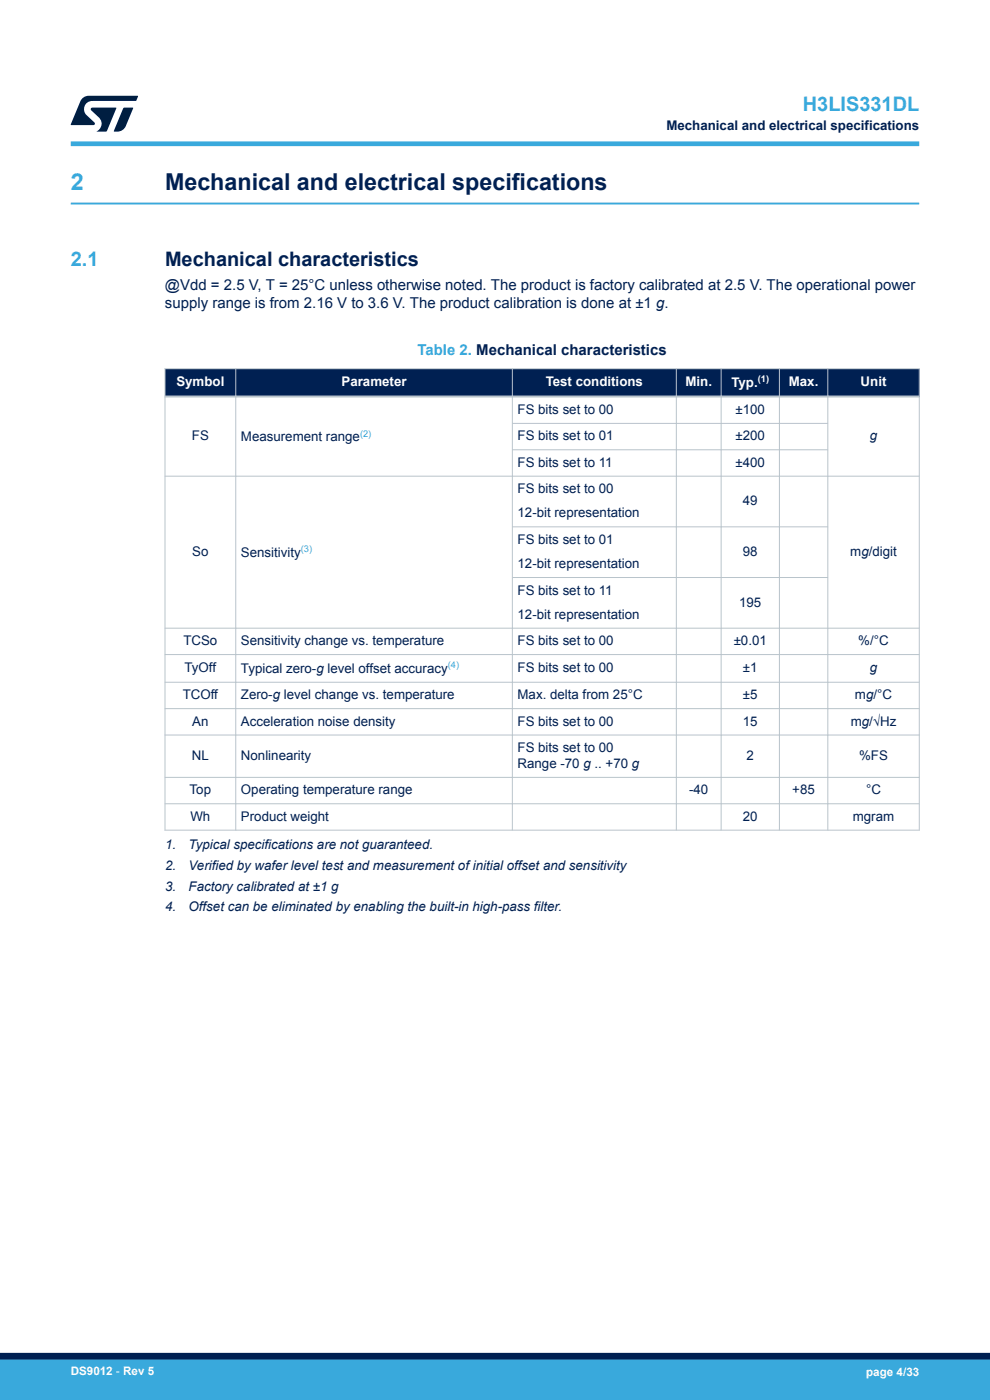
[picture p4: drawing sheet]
<svg xmlns="http://www.w3.org/2000/svg" width="210mm" height="297mm" viewBox="0 0 210 297" stroke-linecap="round" stroke-linejoin="round" font-family="sans-serif">
<defs><g id="words">
<text font-size="4.9" fill="#39a9dc" x="15" y="40.4">2</text>
<text font-size="4.9" fill="#002052" x="35" y="40.4">Mechanical and electrical specifications</text>
<g font-size="4.2" fill="#39a9dc">
<text x="170.3" y="23.5">H3LIS331DL</text>
<text x="15" y="56.4">2.1</text>
</g>
<text font-size="4.2" fill="#002052" x="35" y="56.4">Mechanical characteristics</text>
<g font-size="3.2" fill="#002052">
<text x="35" y="61.5">@Vdd = 2.5 V, T = 25°C unless otherwise noted. The product is factory calibrated at 2.5 V. The operational power</text>
<text x="35" y="65.3">supply range is from 2.16 V to 3.6 V. The product calibration is done at ±1 g.</text>
</g>
<text font-size="3.2" fill="#39a9dc" x="88.6" y="75.2">Table 2. Mechanical characteristics</text>
<g font-size="2.8" fill="#002052">
<text x="141.4" y="27.5">Mechanical and electrical specifications</text>
<text x="109.8" y="87.8">FS bits set to 00</text>
<text x="156" y="87.8">±100</text>
<text x="40.7" y="93.4">FS</text>
<text x="51.1" y="93.6">Measurement range</text>
<text x="109.8" y="93.4">FS bits set to 01</text>
<text x="156" y="93.4">±200</text>
<text x="184.5" y="93.4">g</text>
<text x="109.8" y="99">FS bits set to 11</text>
<text x="156" y="99">±400</text>
<text x="109.8" y="104.6">FS bits set to 00</text>
<text x="157.6" y="107.2">49</text>
<text x="109.8" y="109.8">12-bit representation</text>
<text x="40.8" y="118">So</text>
<text x="51.1" y="118.1">Sensitivity</text>
<text x="109.8" y="115.4">FS bits set to 01</text>
<text x="157.6" y="118">98</text>
<text x="180.4" y="118">mg/digit</text>
<text x="109.8" y="120.5">12-bit representation</text>
<text x="109.8" y="126.1">FS bits set to 11</text>
<text x="109.8" y="131.3">12-bit representation</text>
<text x="156.8" y="128.7">195</text>
<text x="38.9" y="136.9">TCSo</text>
<text x="51.1" y="136.9">Sensitivity change vs. temperature</text>
<text x="109.8" y="136.9">FS bits set to 00</text>
<text x="155.6" y="136.9">±0.01</text>
<text x="182.1" y="136.9">%/°C</text>
<text x="39.2" y="142.6">TyOff</text>
<text x="51.1" y="142.7">Typical zero-g level offset accuracy</text>
<text x="109.8" y="142.6">FS bits set to 00</text>
<text x="157.6" y="142.6">±1</text>
<text x="184.5" y="142.6">g</text>
<text x="38.8" y="148.3">TCOff</text>
<text x="51.1" y="148.3">Zero-g level change vs. temperature</text>
<text x="109.8" y="148.3">Max. delta from 25°C</text>
<text x="157.6" y="148.3">±5</text>
<text x="181.4" y="148.3">mg/°C</text>
<text x="40.8" y="153.9">An</text>
<text x="51.1" y="153.9">Acceleration noise density</text>
<text x="109.8" y="153.9">FS bits set to 00</text>
<text x="157.6" y="153.9">15</text>
<text x="180.4" y="153.9">mg/√Hz</text>
<text x="40.7" y="161.2">NL</text>
<text x="51.1" y="161.2">Nonlinearity</text>
<text x="109.8" y="159.5">FS bits set to 00</text>
<text x="158.4" y="161.2">2</text>
<text x="182.2" y="161.2">%FS</text>
<text x="109.8" y="162.9">Range -70 g .. +70 g</text>
<text x="40.2" y="168.5">Top</text>
<text x="51.1" y="168.5">Operating temperature range</text>
<text x="146.2" y="168.5">-40</text>
<text x="168.1" y="168.5">+85</text>
<text x="183.7" y="168.5">°C</text>
<text x="40.4" y="174.1">Wh</text>
<text x="51.1" y="174.1">Product weight</text>
<text x="157.6" y="174.1">20</text>
<text x="180.9" y="174.1">mgram</text>
<text x="35" y="180.2">1.</text>
<text x="35" y="184.5">2.</text>
<text x="40" y="180.2">Typical specifications are not guaranteed.</text>
<text x="40" y="184.5">Verified by wafer level test and measurement of initial offset and sensitivity</text>
<text x="35" y="188.9">3.</text>
<text x="40" y="188.9">Factory calibrated at ±1 g</text>
<text x="35" y="193.3">4.</text>
<text x="40" y="193.3">Offset can be eliminated by enabling the built-in high-pass filter.</text>
</g>
<g font-size="2.8" fill="#fff">
<text x="37.4" y="81.9">Symbol</text>
<text x="72.4" y="81.9">Parameter</text>
<text x="115.7" y="81.9">Test conditions</text>
<text x="145.4" y="81.9">Min.</text>
<text x="155.1" y="82">Typ.</text>
<text x="167.3" y="81.9">Max.</text>
<text x="182.6" y="81.9">Unit</text>
</g>
<g font-size="2.5" fill="#fff">
<text x="15" y="291.6">DS9012 - Rev 5</text>
<text x="183.7" y="291.9">page 4/33</text>
</g>
<text font-size="2" fill="#fff" x="160.7" y="81.1">(1)</text>
<g font-size="2" fill="#39a9dc">
<text x="76.4" y="92.6">(2)</text>
<text x="63.8" y="117.2">(3)</text>
<text x="95" y="141.8">(4)</text>
</g>
</g></defs>
<path d="M15 43.2h180" fill="none" stroke="#39a9dc" stroke-width=".4"/>
<g fill="#002052">
<path d="M35 78.2h160v5.9h-160z" fill-rule="evenodd"/>
<path d="M35 78.2h160v5.9h-160z" fill-rule="evenodd"/>
</g>
<g fill="none" stroke="#b9c4ca" stroke-width=".21">
<path d="M34.9 78.2h160.2M35 78.1v98.1M50 78.1v98.1M108.7 78.1v98.1M143.5 78.1v98.1M153 78.1v98.1M165.3 78.1v98.1M175.6 78.1v98.1M195 78.1v98.1M108.7 89.8h67M108.7 95.4h67M34.9 101h160.2"/>
<path d="M108.7 111.8h67M34.9 133.3h160.2M34.9 138.9h160.2M108.7 122.5h67M34.9 144.7h160.2M34.9 150.3h160.2M34.9 155.9h160.2M34.9 164.9h160.2M34.9 170.5h160.2M34.9 176.1h160.2"/>
</g>
<path d="M34.9 84.1h160.2" fill="none" stroke="#b9c4ca" stroke-width=".42"/>
<path d="M15 30.5h180" fill="none" stroke="#39a9dc" stroke-width="1"/>
<g fill="#001e41">
<path d="M17.6 20.8l1.2-.5 10.5 .1-.5 1h-9.2a1.74 1.74 0 0 0-1.6 1 1.74 1.74 0 0 0 .3 2l1.7 1.6 .1 .2-.1 .3h-5l2.1-5z"/>
<path d="M26.2 22.9h2.1l-1.6 3.9a1.92 1.92 0 0 1-1.8 1.1h-.7l-.1-.1z"/>
<path d="M19.4 22.9l5.2-.1 .1 .1-2.1 5h-2.1a1.85 1.85 0 0 0 .5-2.9l-1.6-1.6-.2-.2z"/>
</g>
<g fill="#39a9dc">
<path d="M0 288.4h210v8.6h-210z" fill-rule="evenodd"/>
<path d="M-.1 288.4h210.2v4.4h-210.2z" fill-rule="evenodd"/>
</g>
<path d="M0 287.7h210" fill="none" stroke="#002052" stroke-width="1.4"/>
<use href="#words"/>
</svg>
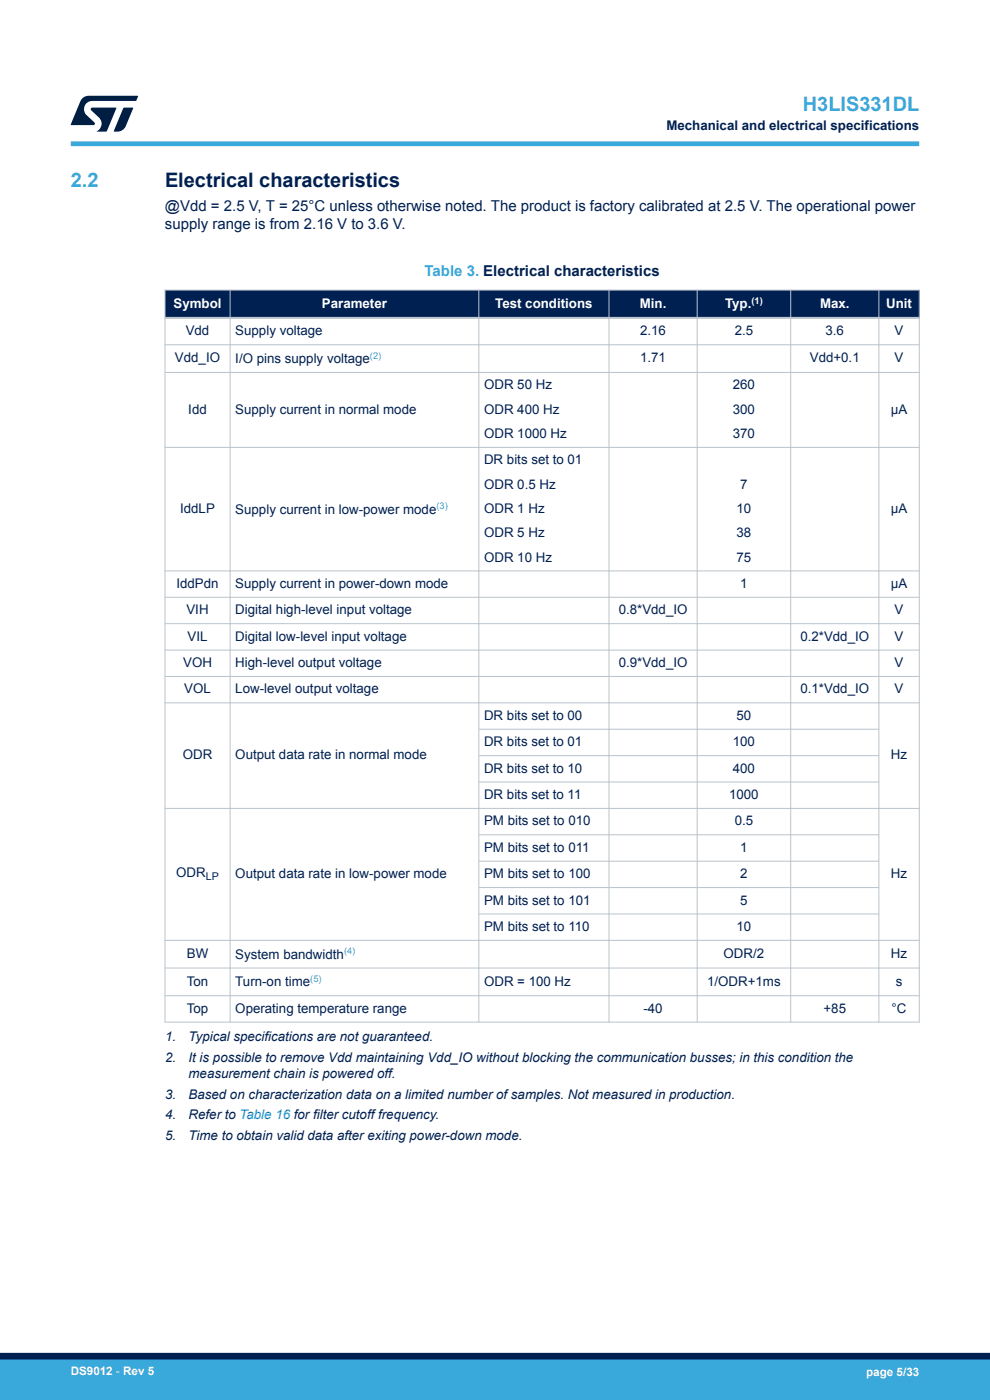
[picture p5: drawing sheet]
<svg xmlns="http://www.w3.org/2000/svg" width="210mm" height="297mm" viewBox="0 0 210 297" stroke-linecap="round" stroke-linejoin="round" font-family="sans-serif">
<defs><g id="words">
<g font-size="4.2" fill="#39a9dc">
<text x="170.3" y="23.5">H3LIS331DL</text>
<text x="15" y="39.8">2.2</text>
</g>
<text font-size="4.2" fill="#002052" x="35" y="39.8">Electrical characteristics</text>
<g font-size="3.2" fill="#002052">
<text x="35" y="44.8">@Vdd = 2.5 V, T = 25°C unless otherwise noted. The product is factory calibrated at 2.5 V. The operational power</text>
<text x="35" y="48.6">supply range is from 2.16 V to 3.6 V.</text>
</g>
<text font-size="3.2" fill="#39a9dc" x="90.1" y="58.6">Table 3. Electrical characteristics</text>
<g font-size="2.8" fill="#002052">
<text x="141.4" y="27.5">Mechanical and electrical specifications</text>
<text x="39.4" y="71.2">Vdd</text>
<text x="49.9" y="71.2">Supply voltage</text>
<text x="135.8" y="71.2">2.16</text>
<text x="155.8" y="71.2">2.5</text>
<text x="175.1" y="71.2">3.6</text>
<text x="189.8" y="71.2">V</text>
<text x="37.1" y="76.9">Vdd_IO</text>
<text x="49.9" y="77">I/O pins supply voltage</text>
<text x="135.8" y="76.9">1.71</text>
<text x="171.8" y="76.9">Vdd+0.1</text>
<text x="189.8" y="76.9">V</text>
<text x="102.7" y="82.6">ODR 50 Hz</text>
<text x="155.5" y="82.6">260</text>
<text x="39.9" y="87.8">Idd</text>
<text x="49.9" y="87.8">Supply current in normal mode</text>
<text x="102.7" y="87.8">ODR 400 Hz</text>
<text x="155.5" y="87.8">300</text>
<text x="189" y="87.8">µA</text>
<text x="102.7" y="92.9">ODR 1000 Hz</text>
<text x="155.5" y="92.9">370</text>
<text x="102.7" y="98.5">DR bits set to 01</text>
<text x="102.7" y="103.7">ODR 0.5 Hz</text>
<text x="157" y="103.7">7</text>
<text x="38.2" y="108.8">IddLP</text>
<text x="49.9" y="109">Supply current in low-power mode</text>
<text x="102.7" y="108.8">ODR 1 Hz</text>
<text x="102.7" y="114">ODR 5 Hz</text>
<text x="156.2" y="108.8">10</text>
<text x="156.2" y="114">38</text>
<text x="189" y="108.8">µA</text>
<text x="102.7" y="119.1">ODR 10 Hz</text>
<text x="156.2" y="119.1">75</text>
<text x="37.4" y="124.7">IddPdn</text>
<text x="49.9" y="124.7">Supply current in power-down mode</text>
<text x="157" y="124.7">1</text>
<text x="189" y="124.7">µA</text>
<text x="39.6" y="130.3">VIH</text>
<text x="49.9" y="130.3">Digital high-level input voltage</text>
<text x="131.2" y="130.3">0.8*Vdd_IO</text>
<text x="189.8" y="130.3">V</text>
<text x="39.8" y="135.9">VIL</text>
<text x="49.9" y="135.9">Digital low-level input voltage</text>
<text x="169.8" y="135.9">0.2*Vdd_IO</text>
<text x="189.8" y="135.9">V</text>
<text x="38.8" y="141.5">VOH</text>
<text x="49.9" y="141.5">High-level output voltage</text>
<text x="131.2" y="141.5">0.9*Vdd_IO</text>
<text x="189.8" y="141.5">V</text>
<text x="39.1" y="147.1">VOL</text>
<text x="49.9" y="147.1">Low-level output voltage</text>
<text x="169.8" y="147.1">0.1*Vdd_IO</text>
<text x="189.8" y="147.1">V</text>
<text x="102.7" y="152.7">DR bits set to 00</text>
<text x="156.2" y="152.7">50</text>
<text x="38.8" y="161.1">ODR</text>
<text x="49.9" y="161.1">Output data rate in normal mode</text>
<text x="102.7" y="158.3">DR bits set to 01</text>
<text x="155.5" y="158.3">100</text>
<text x="189" y="161.1">Hz</text>
<text x="102.7" y="163.9">DR bits set to 10</text>
<text x="155.5" y="163.9">400</text>
<text x="102.7" y="169.5">DR bits set to 11</text>
<text x="154.7" y="169.5">1000</text>
<text x="102.7" y="175.1">PM bits set to 010</text>
<text x="155.8" y="175.1">0.5</text>
<text x="102.7" y="180.7">PM bits set to 011</text>
<text x="157" y="180.7">1</text>
<text x="37.4" y="186.1">ODR</text>
<text x="49.9" y="186.3">Output data rate in low-power mode</text>
<text x="102.7" y="186.3">PM bits set to 100</text>
<text x="102.7" y="191.9">PM bits set to 101</text>
<text x="157" y="186.3">2</text>
<text x="157" y="191.9">5</text>
<text x="189" y="186.3">Hz</text>
<text x="102.7" y="197.5">PM bits set to 110</text>
<text x="156.2" y="197.5">10</text>
<text x="39.6" y="203.2">BW</text>
<text x="49.9" y="203.4">System bandwidth</text>
<text x="153.5" y="203.2">ODR/2</text>
<text x="189" y="203.2">Hz</text>
<text x="39.6" y="209.1">Ton</text>
<text x="49.9" y="209.2">Turn-on time</text>
<text x="102.7" y="209.1">ODR = 100 Hz</text>
<text x="150" y="209.1">1/ODR+1ms</text>
<text x="190" y="209.1">s</text>
<text x="39.6" y="214.8">Top</text>
<text x="49.9" y="214.8">Operating temperature range</text>
<text x="136.5" y="214.8">-40</text>
<text x="174.7" y="214.8">+85</text>
<text x="189.1" y="214.8">°C</text>
<text x="35" y="220.9">1.</text>
<text x="40" y="220.9">Typical specifications are not guaranteed.</text>
<text x="35" y="225.3">2.</text>
<text x="40" y="225.3">It is possible to remove Vdd maintaining Vdd_IO without blocking the communication busses; in this condition the</text>
<text x="35" y="233">3.</text>
<text x="40" y="228.7">measurement chain is powered off.</text>
<text x="40" y="233">Based on characterization data on a limited number of samples. Not measured in production.</text>
<text x="35" y="237.4">4.</text>
<text x="40" y="237.4">Refer to Table 16 for filter cutoff frequency.</text>
<text x="35" y="241.8">5.</text>
<text x="40" y="241.8">Time to obtain valid data after exiting power-down mode.</text>
</g>
<g font-size="2.8" fill="#fff">
<text x="36.8" y="65.3">Symbol</text>
<text x="68.3" y="65.3">Parameter</text>
<text x="105.1" y="65.3">Test conditions</text>
<text x="135.7" y="65.3">Min.</text>
<text x="153.8" y="65.3">Typ.</text>
<text x="173.9" y="65.3">Max.</text>
<text x="188" y="65.3">Unit</text>
</g>
<g font-size="2.5" fill="#fff">
<text x="15" y="291.6">DS9012 - Rev 5</text>
<text x="183.7" y="291.9">page 5/33</text>
</g>
<text font-size="2.3" fill="#002052" x="43.7" y="186.6">LP</text>
<text font-size="2" fill="#fff" x="159.4" y="64.4">(1)</text>
<g font-size="2" fill="#39a9dc">
<text x="78.5" y="76.1">(2)</text>
<text x="92.6" y="108">(3)</text>
<text x="73" y="202.4">(4)</text>
<text x="65.8" y="208.3">(5)</text>
</g>
</g></defs>
<g fill="#002052">
<path d="M35 61.5h160v5.9h-160z" fill-rule="evenodd"/>
<path d="M35 61.5h160v5.9h-160z" fill-rule="evenodd"/>
</g>
<g fill="none" stroke="#b9c4ca" stroke-width=".21">
<path d="M34.9 61.5h160.2M34.9 73.1h160.2M34.9 79h160.2M35 61.4v155.5M48.8 61.4v155.5M101.6 61.4v155.5M129.2 61.4v155.5M147.9 61.4v155.5M167.7 61.4v155.5M186.4 61.4v155.5M195 61.4v155.5M34.9 94.9h160.2"/>
<path d="M34.9 121.1h160.2M34.9 126.7h160.2M34.9 132.3h160.2M34.9 137.9h160.2M34.9 143.5h160.2M34.9 149.1h160.2M101.6 154.7h84.9M34.9 171.5h160.2M101.6 160.3h84.9M101.6 165.9h84.9M101.6 177.1h84.9M34.9 199.5h160.2"/>
<path d="M101.6 182.7h84.9M101.6 188.3h84.9M101.6 193.9h84.9M34.9 205.4h160.2M34.9 211.2h160.2M34.9 216.8h160.2"/>
</g>
<path d="M34.9 67.4h160.2" fill="none" stroke="#b9c4ca" stroke-width=".42"/>
<path d="M15 30.5h180" fill="none" stroke="#39a9dc" stroke-width="1"/>
<g fill="#001e41">
<path d="M17.6 20.8l1.2-.5 10.5 .1-.5 1h-9.2a1.74 1.74 0 0 0-1.6 1 1.74 1.74 0 0 0 .3 2l1.7 1.6 .1 .2-.1 .3h-5l2.1-5z"/>
<path d="M26.2 22.9h2.1l-1.6 3.9a1.92 1.92 0 0 1-1.8 1.1h-.7l-.1-.1z"/>
<path d="M19.4 22.9l5.2-.1 .1 .1-2.1 5h-2.1a1.85 1.85 0 0 0 .5-2.9l-1.6-1.6-.2-.2z"/>
</g>
<g fill="#39a9dc">
<path d="M0 288.4h210v8.6h-210z" fill-rule="evenodd"/>
<path d="M-.1 288.4h210.2v4.4h-210.2z" fill-rule="evenodd"/>
</g>
<path d="M0 287.7h210" fill="none" stroke="#002052" stroke-width="1.4"/>
<use href="#words"/>
</svg>
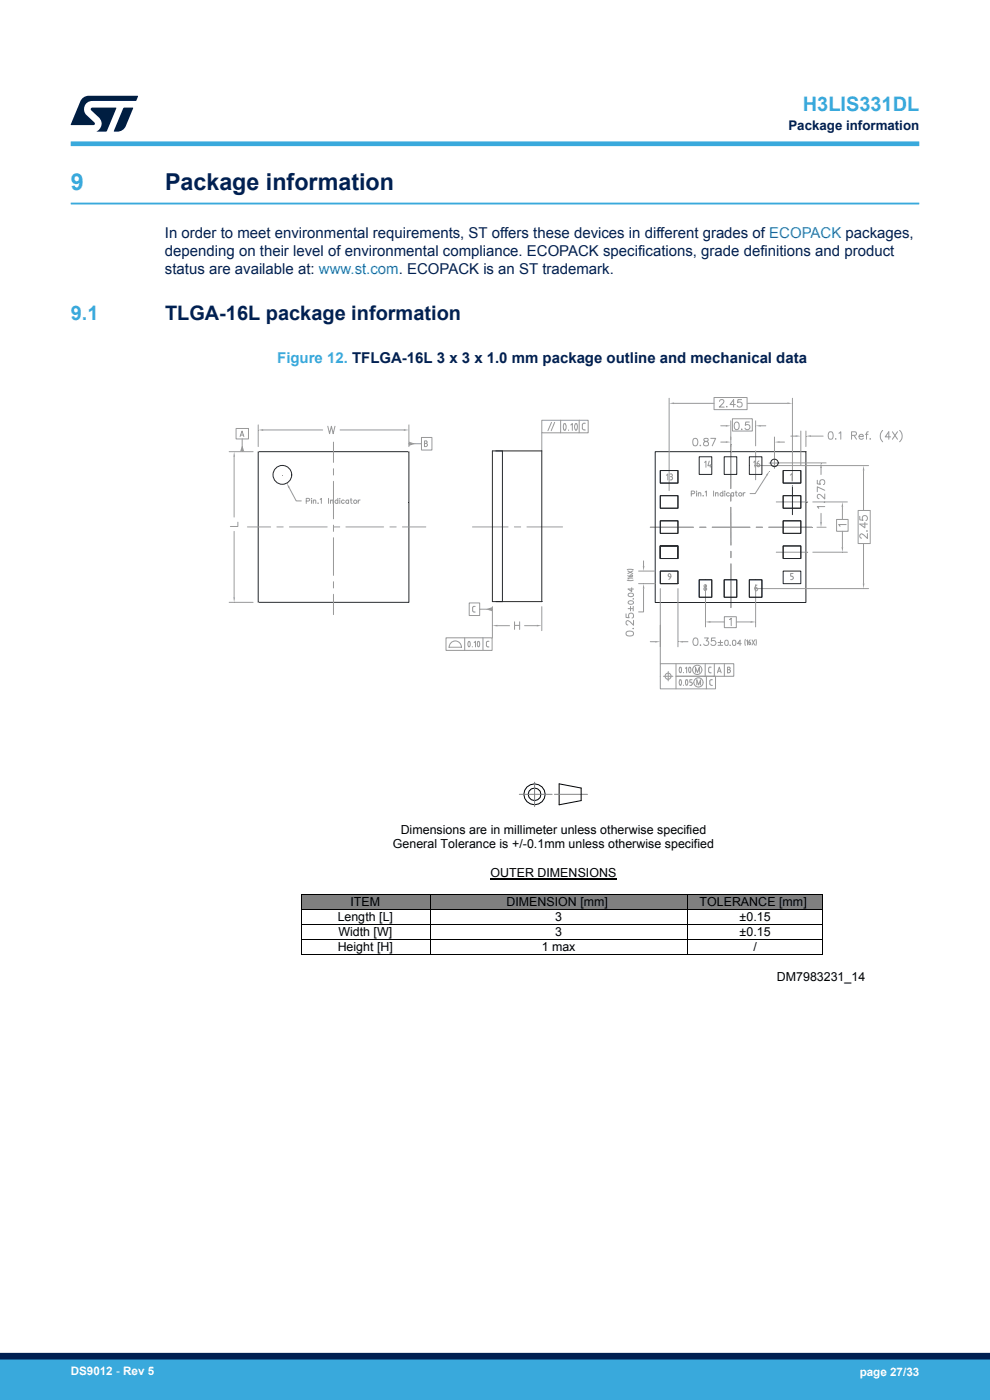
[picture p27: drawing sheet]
<svg xmlns="http://www.w3.org/2000/svg" width="210mm" height="297mm" viewBox="0 0 210 297" stroke-linecap="round" stroke-linejoin="round" font-family="sans-serif">
<defs><g id="words">
<text font-size="4.9" fill="#39a9dc" x="15" y="40.4">9</text>
<text font-size="4.9" fill="#002052" x="35" y="40.4">Package information</text>
<g font-size="4.2" fill="#39a9dc">
<text x="170.3" y="23.5">H3LIS331DL</text>
<text x="15" y="67.9">9.1</text>
</g>
<text font-size="4.2" fill="#002052" x="35" y="67.9">TLGA-16L package information</text>
<g font-size="3.2" fill="#002052">
<text x="35" y="50.5">In order to meet environmental requirements, ST offers these devices in different grades of ECOPACK packages,</text>
<text x="35" y="54.3">depending on their level of environmental compliance. ECOPACK specifications, grade definitions and product</text>
<text x="35" y="58.1">status are available at: www.st.com. ECOPACK is an ST trademark.</text>
</g>
<text font-size="3.2" fill="#39a9dc" x="58.8" y="77">Figure 12. TFLGA-16L 3 x 3 x 1.0 mm package outline and mechanical data</text>
<text font-size="2.8" fill="#002052" x="167.2" y="27.5">Package information</text>
<g font-size="2.6">
<text x="85" y="177">Dimensions are in millimeter unless otherwise specified</text>
<text x="83.3" y="180">General Tolerance is +/-0.1mm unless otherwise specified</text>
<text x="104" y="186.1">OUTER DIMENSIONS</text>
<text x="71.6" y="195.5">Length [L]</text>
<text x="74.4" y="192.3">ITEM</text>
<text x="107.4" y="192.3">DIMENSION [mm]</text>
<text x="117.8" y="195.5">3</text>
<text x="148.4" y="192.3">TOLERANCE [mm]</text>
<text x="156.9" y="195.5">±0.15</text>
<text x="71.6" y="201.8">Height [H]</text>
<text x="71.8" y="198.6">Width [W]</text>
<text x="114.9" y="201.8">1 max</text>
<text x="117.8" y="198.6">3</text>
<text x="156.9" y="198.6">±0.15</text>
<text x="159.8" y="201.8">/</text>
<text x="164.8" y="208.2">DM7983231_14</text>
</g>
<g font-size="2.5" fill="#fff">
<text x="15" y="291.6">DS9012 - Rev 5</text>
<text x="182.4" y="291.9">page 27/33</text>
</g>
</g></defs>
<path d="M15 43.2h180" fill="none" stroke="#39a9dc" stroke-width=".4"/>
<path d="M155 94.3v9.3M137.9 111.9h9.2M148.4 111.9h1.3M151.1 111.9h8M155 107.6v8M155 105v1.3M155 117v1.3M155 119.6v9.3M160.4 111.9h1.3M163.1 111.9h9.1" fill="none" stroke="#999" stroke-width=".21"/>
<path d="M54.8 95.8h31.9v32h-31.9z" fill="none" stroke="#222831" stroke-width=".21"/>
<path d="M54.8 90.1v4.6M55.8 91.2h12.7M72.1 91.2h13.6M86.7 90.1v4.6" fill="none" stroke="#999" stroke-width=".21"/>
<g fill="#999">
<path d="M85.7 91l1 .2-1 .2z"/>
<path d="M54.8 91.2l1-.2v.4z"/>
</g>
<path d="M48.6 95.8h5.1M49.7 96.9v12.8M69.5 90.4l.4 1.6 .4-1.6 .4 1.6 .4-1.6M49.7 112.7v14M48.6 127.8h5.1" fill="none" stroke="#999" stroke-width=".21"/>
<g fill="#999">
<path d="M49.7 95.8l.2 1.1h-.4z"/>
<path d="M49.5 126.7h.4l-.2 1.1z"/>
</g>
<g fill="none" stroke="#999" stroke-width=".21">
<path d="M70.7 93.8v4.3M70.7 99.4v1.4M50.5 110.8v.9h-1.6M52.5 111.8h4.9M58.7 111.8h1.4M61.4 111.8h8M70.7 102.1v8M70.7 111.4v1.3M70.7 114.1v8M70.7 111.8h1.4M73.4 111.8h8M82.7 111.8h1.3"/>
<path d="M85.4 111.8h4.9M70.7 123.4v1.3M70.7 126.1v4.3M104.4 128.7v5.1M105.5 132.7h2.6M111.3 132.7h2.6M114.9 128.7v5.1"/>
</g>
<g fill="#999">
<path d="M113.9 132.5l1 .2-1 .2z"/>
<path d="M104.4 132.7l1.1-.2v.4z"/>
</g>
<path d="M86.7 94.1h2.7M89.4 92.8h2.2v2.7h-2.2zM90 94.1l.6 .1v.3l-.2 .2M90.4 94h.1v-.4l-.5-.1v1.2h.4M109.1 131.9v1.6M109.1 132.7h1.1M110.2 131.9v1.6" fill="none" stroke="#999" stroke-width=".21"/>
<path d="M86.7 93.7l1.4 .4-1.4 .5z" fill="#999"/>
<path d="M50.1 90.9h2.6v2.2h-2.6zM50.9 92.6l.4-1.2 .4 1.2M51.1 92.3h.5M51.4 93.1v2.7" fill="none" stroke="#999" stroke-width=".21"/>
<path d="M51.4 94.5l.4 1.3h-.9z" fill="#999"/>
<path d="M99.5 127.9h2.3v2.7h-2.3zM100.5 129.8h.3M100.8 128.6l-.4 .1-.1 .2v.8l.2 .1M101.8 129.2h2.6" fill="none" stroke="#999" stroke-width=".21"/>
<path d="M103.1 129.2l1.3-.4v.9z" fill="#999"/>
<g fill="none" stroke="#999" stroke-width=".21">
<path d="M114.9 89.2h9.9v2.6h-9.9zM114.9 91.8v3.9M117 89.6l-.8 1.8M117.7 89.6l-.8 1.8M118.9 89.2v2.6M119.6 89.9h.1a.81 .81 0 0 1 0 1.4l-.2-.5zM120.6 91.2v.1M121.1 90.2l.3-.3v1.4M122.1 89.9a.8 .8 0 0 1 .2 1.3v.1a.9 .9 0 0 1-.2-1.4zM122.9 89.2v2.6M123.9 91.2h.3M124.2 89.8h-.5l-.2 .3v.8l.4 .3"/>
<path d="M155 94.3v9.3M100.2 111.8h7.6M109.1 111.8h1.3M111.8 111.8h7.5M137.9 111.9h9.2M148.4 111.9h1.3M151.1 111.9h8M155 107.6v8M155 105v1.3M155 117v1.3M155 119.6v9.3M160.4 111.9h1.3"/>
<path d="M163.1 111.9h9.1M94.6 135.3h9.8v2.7h-9.8zM95.8 136.2a1.3 1.3 0 0 1 1.4-.1 1.3 1.3 0 0 1 .7 1.2h-2.6v-.4zM98.6 135.3v2.7M99.4 136.1a.63 .63 0 0 1 0 1.1l-.2-.6 .2-.5M100.2 137.2h.1M100.6 136.3l.3-.3v1.2M101.4 136.1a.63 .63 0 0 1 0 1.1l-.2-.6 .2-.5M102.4 135.3v2.7M103.5 137.2h.2M103.5 136h.2M103.5 136.1l-.3 .3v.7l.3 .1"/>
<path d="M104.4 133.8v1.5"/>
</g>
<path d="M139 95.8h31.9v32h-31.9zM140 115.8h3.8v2.7h-3.8zM168.1 103.1v6.1" fill="none" stroke="#222831" stroke-width=".21"/>
<path d="M160.3 95.7v6.1M136.5 119v1.1M164.7 106.5h6.6M164.7 117.2h6.6M135.5 121.2h3.5M135.5 123.8h3.5M136.5 124.9v4.9h-1" fill="none" stroke="#999" stroke-width=".21"/>
<g fill="#999">
<path d="M136.4 120.1h.3l-.2 1.1z"/>
<path d="M136.5 123.8l.2 1.1h-.3z"/>
</g>
<path d="M132.8 130.2v.8l.7 .1a.56 .56 0 0 1-.1-.9 .56 .56 0 0 1 .9 .1 .56 .56 0 0 1-.2 .8M132.9 134.1l.6-.2a.68 .68 0 0 1 .9 .6 .93 .93 0 0 1-1.6 0zM133.2 129.1h1M133.3 127.6l.4-.2 .6 .2a.56 .56 0 0 1-.4 .7 .56 .56 0 0 1-.7-.4zM133.3 126a.56 .56 0 0 1 .7-.2 .56 .56 0 0 1 .3 .6 .56 .56 0 0 1-.7 .2 .56 .56 0 0 1-.3-.6zM133.7 128.6v1M134.3 127v.1M134.3 128.6v1M134.3 133.3h-.1M134.4 131.6v1l-.8-.7-.5-.2-.2 .1-.1 .5 .1 .2 .3 .1" fill="none" stroke="#999" stroke-width=".21"/>
<path d="M134 124.7v.8l-.8-.5h1.2M149.7 124v9M150.7 131.9h2.9M156.2 131.9h3M160.3 124v9" fill="none" stroke="#999" stroke-width=".21"/>
<g fill="#999">
<path d="M149.7 131.9l1-.1v.3z"/>
<path d="M159.2 131.8l1.1 .1-1.1 .2z"/>
</g>
<path d="M162.7 100.8l-2.5 3.9h-1.1M154.7 131.4l.4-.3v1.6" fill="none" stroke="#999" stroke-width=".21"/>
<path d="M163.2 99.9l-.4 1-.3-.2z" fill="#999"/>
<g fill="none" stroke="#999" stroke-width=".21">
<path d="M146.6 104.7h.6l.1-.4-.7-.1v1M147.7 104.5v.7M147.7 104.2h.1M148.1 104.5v.7M148.1 104.7l.3-.2 .2 .1 .1 .6M149.1 105.2h.1M149.6 104.4l.2-.2v1M151.4 104.2v1M151.8 104.5v.7M151.8 104.7l.2-.2 .3 .1v.6M153.3 104.2v1M153.3 104.7a.34 .34 0 0 0-.5-.1 .34 .34 0 0 0 0 .5 .34 .34 0 0 0 .5 0"/>
<path d="M153.7 104.5v.7M153.7 104.2h.1M154.7 104.7a.34 .34 0 0 0-.5-.1 .34 .34 0 0 0 0 .5 .34 .34 0 0 0 .5 0M155.6 104.5v.7M155.6 104.7a.34 .34 0 0 0-.5-.1 .34 .34 0 0 0 0 .5 .34 .34 0 0 0 .5 0M156 104.5h.3M156.1 104.2v.8l.3 .2"/>
<circle cx="157" cy="104.9" r=".36"/>
</g>
<path d="M152.9 90.3h1.1M155 89.3v4M160.3 89.3v5.3M161.4 90.3h1M157.6 104.5v.7M158.1 104.5l-.5 .3" fill="none" stroke="#999" stroke-width=".21"/>
<g fill="#999">
<path d="M154 90.2l1 .1-1 .2z"/>
<path d="M160.3 90.3l1.1-.1v.3z"/>
</g>
<path d="M156 89.6a.49 .49 0 0 1 .7 .3l.1 .3a.68 .68 0 0 1-.6 1 1.04 1.04 0 0 1-.2-1.6z" fill="none" stroke="#999" stroke-width=".21"/>
<path d="M141.9 84.5v19.6M143 85.6h8.5M155.4 88.8h4.2v2.6h-4.2zM157.3 91v.2l.1-.1M158.5 85.6h8.5M159 89.5h-.8l-.1 .7a.56 .56 0 0 1 .8 0 .56 .56 0 0 1-.1 .8 .56 .56 0 0 1-.8-.2M168.1 84.5v17.5" fill="none" stroke="#999" stroke-width=".21"/>
<g fill="#999">
<path d="M141.9 85.6l1.1-.2v.3z"/>
<path d="M167 85.4l1.1 .2-1.1 .1z"/>
</g>
<path d="M151.5 84.3h7v2.6h-7zM152.6 85.2l.4-.4 .5 .1v.5l-.9 1h1M154.2 86.2v.2l.1-.1M156 85.8h-1.1l.7-1v1.6M157.3 84.8h-.8l-.1 .6a.56 .56 0 0 1 .9 0 .56 .56 0 0 1-.1 .9 .56 .56 0 0 1-.8-.3M172.4 106.5h7.3M172.4 117.2h7.3M178.7 107.5v2.7M178.7 112.7v3.4" fill="none" stroke="#999" stroke-width=".21"/>
<g fill="#999">
<path d="M178.7 106.5l.2 1h-.4z"/>
<path d="M178.5 116.1h.4l-.2 1.1z"/>
</g>
<path d="M179.5 111.3h-1.6l.3 .4M137.9 136.1h1.1M140.1 124.9v12.3M143.8 124.9v12.3M144.9 136.1h1" fill="none" stroke="#999" stroke-width=".21"/>
<g fill="#999">
<path d="M139 136l1.1 .1-1.1 .2z"/>
<path d="M143.8 136.1l1.1-.1v.3z"/>
</g>
<path d="M147.2 135.4a.54 .54 0 0 1 .8 .3v.9a.51 .51 0 0 1-.5 .3 .51 .51 0 0 1-.4-.3 1.22 1.22 0 0 1 .1-1.2zM148.6 136.8l-.1 .1h.2M149.4 135.3h.9l-.5 .6a.53 .53 0 0 1 .4 .9 .53 .53 0 0 1-.9-.2M151.7 135.3h-.7l-.1 .7a.57 .57 0 0 1 .8 0 .57 .57 0 0 1-.1 .9 .57 .57 0 0 1-.8-.3M152.3 136.3h1M152.3 136.9h1M152.8 135.8v1M153.9 135.8h.2a.58 .58 0 0 1 .4 .6 .58 .58 0 0 1-.4 .5l-.3-.2-.1-.2zM154.9 136.8v.1M155.5 135.8h.2a.58 .58 0 0 1 .4 .6 .58 .58 0 0 1-.4 .5l-.3-.2z" fill="none" stroke="#999" stroke-width=".21"/>
<g fill="none" stroke="#999" stroke-width=".21">
<path d="M160 98.8h24.3M183.2 99.8v8.5M183.2 115.3v8.5M133 123.1h1.3M133 120.8l1.3 .1M133.2 121.1l1 .6M133.2 122.1l.4 .2M133.7 122h.3l.2 .2-.6 .2zM134.2 121.1l-1 .6M134.2 122.6h-1l.2 .2M157.2 136.5h-.8l.6-.7v1.1M158.1 135.6v1.3"/>
<path d="M158.4 136l.2-.2v1M158.9 136.2v.5l.3-.1M158.9 136.2l.3 .1v.2M159.1 135.8l-.2 .4M159.2 136.5v.1M159.5 135.8l.6 1M160 124.9h24.3M160.1 135.8l-.6 1M160.3 135.7v1.2"/>
</g>
<g fill="#999">
<path d="M183.2 98.8l.2 1h-.4z"/>
<path d="M183 123.8h.4l-.2 1.1z"/>
</g>
<g fill="none" stroke="#999" stroke-width=".21">
<path d="M163.1 98.2h2.2M164.3 97.2v2.2M165.4 98.2h9.8M174.2 99.3v1.4M173.3 111.9h1.9M174.2 108.9v1.9M182.4 109.5v.8l.7 .1a.57 .57 0 0 1 0-.9 .57 .57 0 0 1 .8 .1 .57 .57 0 0 1-.2 .9M183.5 110.8v1.2l-1.1-.8h1.6M183.9 112.6h.1h-.2M184 113.2v1l-1.1-1-.5 .4v.3l.4 .3M140.1 132.6v8.2M140.7 143.5h2"/>
<path d="M141.7 142.4v2M143.4 140.8v2.7h8.4v2.6h-11.7v-5.3h15.6v2.7h-12.3v2.6M144.4 142.6a.58 .58 0 0 0 .3-.6 .58 .58 0 0 0-.5-.4 .6 .6 0 0 0-.2 .6 .6 .6 0 0 0 .4 .4M144.4 144.3l.2 .5-.2 .5M144.4 144.3v-.1a.66 .66 0 0 0 0 1.2v-.1M145 142.7h.1M145 145.3v.1M145.4 141.8l.3-.3v1.2M145.6 145.3v.1a.66 .66 0 0 0 0-1.2l-.2 .6 .1 .5M146.3 145.4h.3M146.4 142.6v.1a.67 .67 0 0 1 0-1.2l.2 .6-.2 .5M146.8 144.2h-.5v.5l.5 .1 .1 .2-.3 .4"/>
<path d="M146.9 142.1a.98 .98 0 0 0 1.4 .9 .98 .98 0 0 0 .3-1.6 .98 .98 0 0 0-1.6 .3l-.1 .4M147.5 142.6v-1l.4 1 .4-1v1M147.8 145.3v-1.1l.4 1.1 .4-1.1v1.1M149.6 140.8v2.7M149.8 143.5v2.6M150.6 142.7h.3M150.9 141.5l-.4 .1-.2 .2 .1 .8 .2 .1M150.9 145.4h.2M151.1 144.2h-.4l-.1 .3v.6l.3 .3M151.5 140.8v2.7M152.2 142.7l.4-1.2 .4 1.2M152.3 142.4h.6"/>
<path d="M153.6 140.8v2.7M154.3 142.1h.3a.32 .32 0 0 1 .4 .3 .32 .32 0 0 1-.4 .3M154.6 142l.3-.2-.1-.2-.5-.1v1.2h.3"/>
<circle cx="141.7" cy="143.4" r=".64"/>
<circle cx="148.2" cy="144.8" r=".98"/>
</g>
<g fill="#999">
<path d="M174 110.8h.3l-.1 1.1z"/>
<path d="M174.2 98.2l.1 1.1h-.3z"/>
</g>
<path d="M167.7 92.5h1.1M169.9 91.4v7.3M170.9 91.4v3.3M172 92.5h2.6M173.4 101.9v.7l.6 .1a.56 .56 0 0 1 0-.8 .56 .56 0 0 1 .9 .1 .56 .56 0 0 1-.2 .8M174.9 106.5h-.1M174.9 107.5h-1.5l.3 .4M174.9 104l-1.5-.7v1M174.9 104.8v1.1l-.7-.8-.5-.2-.3 .1v.5l.3 .3" fill="none" stroke="#999" stroke-width=".21"/>
<g fill="#999">
<path d="M168.8 92.3l1.1 .2-1.1 .2z"/>
<path d="M170.9 92.5l1.1-.2v.4z"/>
</g>
<path d="M175.9 91.7a.53 .53 0 0 1 .8 .2v.4a.68 .68 0 0 1-.4 .9h-.2a1.03 1.03 0 0 1-.2-1.5z" fill="none" stroke="#999" stroke-width=".21"/>
<g fill="none" stroke="#999" stroke-width=".21">
<path d="M149.5 98.1l.2-.3v1.3M150.4 97.8l-.2 1h.7M150.7 98.5v.6M152.9 93.8h1.1M155 92.7v2M159.9 98.1l.3-.3v1.3M160.6 98.4l.1 .6h.3l.1-.2M160.6 98.4h.3M160.9 98.4l.2 .2M161 97.8l-.4 .6M161.2 98.6v.2M164.3 92.7v4.5"/>
<path d="M165.4 93.8h1M177.3 93.1h.1M178 91.9l.3-.3v1.6M180.6 92.4l1-.1 .1-.3-.1-.3-1-.1v1.6M181.1 92.4l.6 .8M182.2 92.6h.9a.51 .51 0 0 0-.5-.4 .51 .51 0 0 0-.5 .5 .51 .51 0 0 0 .5 .5l.5-.2M183.6 92.1h.5M184.2 91.6l-.3 .1-.1 .2v1.3M184.6 93.1h.1M187.2 91.3a1.67 1.67 0 0 0 0 2.4M188.9 92.7h-1.1l.7-1.1v1.6M189.3 91.6l1.1 1.6"/>
<path d="M190.4 91.6l-1.1 1.6M190.8 91.3a1.6 1.6 0 0 1 0 2.4M141.4 100.8l.3-.3v1.3M142.1 100.5l.5 .1v.3l-.2 .2M142.1 101.8h.3M142.2 101.1a.34 .34 0 0 1 .4 .3 .34 .34 0 0 1-.2 .4M167.6 100.8l.4-.3v1.6M142 122.4h.3M142.3 122.4l-.4 .5M142.3 122l-.3-.3a.34 .34 0 0 0-.3 .3 .34 .34 0 0 0 .3 .4M142.3 122v.4M149.3 125l.3 .3 .3-.3"/>
<path d="M149.4 124.9v.1M149.9 124.9a.27 .27 0 0 0-.3-.3 .27 .27 0 0 0-.3 .3M149.9 124.9v.1M160.2 124.7v.6h.3l.2-.2M160.2 124.7h.4l.1 .2M160.6 124.1l-.2 .1-.2 .5M160.7 125v.1M167.7 123h.3M168 122.3l.3 .2-.3 .4M168.2 121.7h-.5v.5h.3"/>
<circle cx="149.6" cy="124.3" r=".26"/>
</g>
<g fill="none" stroke="#222831" stroke-width=".21">
<path d="M140.1 99.8h3.7v2.7h-3.7zM148.3 96.9h2.7v3.7h-2.7zM153.6 96.9h2.7v3.7h-2.7zM159 96.9h2.6v3.7h-2.6zM166.1 99.8h3.8v2.7h-3.8zM140.1 110.5h3.7v2.7h-3.7zM140.1 115.8h3.7v2.7h-3.7zM140.1 105.2h3.7v2.6h-3.7zM166.1 110.5h3.8v2.7h-3.8zM166.1 115.8h3.8v2.7h-3.8zM166.1 105.2h3.8v2.6h-3.8zM140.1 121.2h3.7v2.6h-3.7z"/>
<path d="M148.3 123h2.7v3.7h-2.7zM153.6 123h2.7v3.7h-2.7zM159 123h2.6v3.7h-2.6zM166.1 121.2h3.8v2.6h-3.8z"/>
<circle cx="164.3" cy="98.2" r=".79"/>
</g>
<g fill="#999">
<path d="M164.3 93.8l1.1-.2v.3z"/>
<path d="M154 93.6l1 .2-1 .1z"/>
</g>
<path d="M147.2 93.1a.55 .55 0 0 1 .7 .2 .77 .77 0 0 1 .1 .9 .77 .77 0 0 1-.8 .3l-.2-.6zM148.5 94.4v.2l.1-.1M149.4 93.1a.31 .31 0 0 0 .1 .5l.3 .1a.46 .46 0 0 1 .5 .4 .46 .46 0 0 1-.4 .5h-.3a.46 .46 0 0 1-.4-.5 .46 .46 0 0 1 .5-.4l.5-.2v-.3a.62 .62 0 0 0-.8-.1z" fill="none" stroke="#999" stroke-width=".21"/>
<path d="M150.8 93h1l-.7 1.6M61.3 103.5l1.5 2.8h1.1M177.5 110.2h2.4v2.5h-2.4zM182 108.3h2.6v7h-2.6zM153.6 130.8h2.6v2.3h-2.6z" fill="none" stroke="#999" stroke-width=".21"/>
<g fill="none" stroke="#222831" stroke-width=".21">
<path d="M104.4 95.7h10.5v31.9h-10.5zM106.6 95.7v31.9"/>
<circle cx="59.9" cy="100.7" r="1.99"/>
</g>
<path d="M60.8 102.5l.7 .9-.3 .2z" fill="#999"/>
<g fill="none" stroke="#999" stroke-width=".21">
<path d="M65 106.3l.6-.1v-.4l-.6-.1v1.1M66 105.8h.1M66.1 106.1v.7M66.5 106.3l.2-.2h.3v.7M66.5 106.1v.7M67.5 106.7h.1M67.9 105.9l.3-.2v1.1M69.7 105.7v1.1M70.1 106.1v.7M70.1 106.3l.3-.2h.2v.7M71.7 105.7v1.1M71.7 106.2a.34 .34 0 0 0-.5 0 .34 .34 0 0 0 0 .5 .34 .34 0 0 0 .5-.1"/>
<path d="M72 105.8h.1M72.1 106.1v.7M73 106.2a.34 .34 0 0 0-.5 0 .34 .34 0 0 0 0 .5 .34 .34 0 0 0 .5-.1M73.9 106.2a.34 .34 0 0 0-.5 0 .34 .34 0 0 0 0 .5 .34 .34 0 0 0 .5-.1M73.9 106.1v.7M74.3 106.1h.4M74.5 105.7v.9l.2 .2"/>
<circle cx="75.3" cy="106.4" r=".36"/>
</g>
<path d="M76 106.1v.7M76.4 106.1l-.4 .3" fill="none" stroke="#999" stroke-width=".21"/>
<path d="M104 186.5h26.8" fill="none" stroke="#000" stroke-width=".29"/>
<g fill="#808080">
<path d="M63.9 189.8h27.2v3.1h-27.2z"/>
<path d="M65.3 189.8h24.5v3.1h-24.5z"/>
<path d="M91.3 189.8h54.5v3.1h-54.5z"/>
<path d="M92.6 189.8h51.8v3.1h-51.8z"/>
<path d="M145.9 189.8h28.6v3.1h-28.6z"/>
<path d="M147.3 189.8h25.8v3.1h-25.8z"/>
</g>
<g fill="#000">
<path d="M63.8 189.7l.1 .1zM63.8 192.9l.1 .1zM63.8 196l.1 .2zM63.8 199.2l.1 .1zM91.2 189.7l.1 .1zM91.2 192.9l.1 .1zM91.2 196l.1 .2zM91.2 199.2l.1 .1zM145.8 189.7l.1 .1zM145.8 192.9l.1 .1zM145.8 196l.1 .2zM145.8 199.2l.1 .1z"/>
<path d="M174.5 189.7l.1 .1zM174.5 192.9l.1 .1zM174.5 196l.1 .2zM174.5 199.2l.1 .1zM63.8 202.4l.1 .1zM91.2 202.4l.1 .1zM145.8 202.4l.1 .1zM174.5 202.4l.1 .1z"/>
</g>
<g fill="none" stroke="#000" stroke-width=".21">
<path d="M118.6 166.3l4.7 .9v2.6l-4.7 .9zM63.8 189.8v3.1M63.8 193v3M63.8 196.2v3M63.8 199.3v3.1M63.9 189.7h27.3M63.9 192.9h27.3M63.9 196.1h27.3M63.9 199.3h27.3M91.2 189.8v3.1M91.2 193v3M91.2 196.2v3"/>
<path d="M91.2 199.3v3.1M91.3 189.7h54.5M91.3 192.9h54.5M91.3 196.1h54.5M91.3 199.3h54.5M145.9 189.8v3.1M145.9 193v3M145.9 196.2v3M145.9 199.3v3.1M145.9 189.7h28.6M145.9 192.9h28.6M145.9 196.1h28.6"/>
<path d="M145.9 199.3h28.6M174.5 189.8v3.1M174.5 193v3M174.5 196.2v3M174.5 199.3v3.1M63.9 202.4h27.3M91.3 202.4h54.5M145.9 202.4h28.6"/>
<circle cx="113.4" cy="168.5" r="1.34"/>
<circle cx="113.4" cy="168.5" r="2.24"/>
</g>
<path d="M110.2 168.5h6.9M113.4 165.9v5.2M117.6 168.5h7" fill="none" stroke="#808080" stroke-width=".21"/>
<path d="M15 30.5h180" fill="none" stroke="#39a9dc" stroke-width="1"/>
<g fill="#001e41">
<path d="M17.6 20.8l1.2-.5 10.5 .1-.5 1h-9.2a1.74 1.74 0 0 0-1.6 1 1.74 1.74 0 0 0 .3 2l1.7 1.6 .1 .2-.1 .3h-5l2.1-5z"/>
<path d="M26.2 22.9h2.1l-1.6 3.9a1.92 1.92 0 0 1-1.8 1.1h-.7l-.1-.1z"/>
<path d="M19.4 22.9l5.2-.1 .1 .1-2.1 5h-2.1a1.85 1.85 0 0 0 .5-2.9l-1.6-1.6-.2-.2z"/>
</g>
<g fill="#39a9dc">
<path d="M0 288.4h210v8.6h-210z" fill-rule="evenodd"/>
<path d="M-.1 288.4h210.2v4.4h-210.2z" fill-rule="evenodd"/>
</g>
<path d="M0 287.7h210" fill="none" stroke="#002052" stroke-width="1.4"/>
<use href="#words"/>
</svg>
